VERSION 5.7 ;
BUSBITCHARS "[]" ;
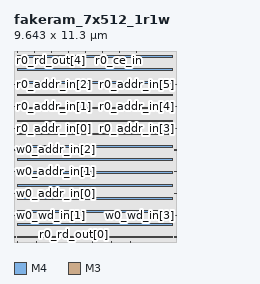
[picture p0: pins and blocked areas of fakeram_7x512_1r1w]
MACRO fakeram_7x512_1r1w
  FOREIGN fakeram_7x512_1r1w 0 0 ;
  SYMMETRY X Y R90 ;
  SIZE 9.643 BY 11.300 ;
  CLASS BLOCK ;
  PIN w0_wd_in[0]
    DIRECTION INPUT ;
    USE SIGNAL ;
    SHAPE ABUTMENT ;
    PORT
      LAYER M4 ;
      RECT 0.000 0.276 0.072 0.300 ;
    END
  END w0_wd_in[0]
  PIN w0_wd_in[1]
    DIRECTION INPUT ;
    USE SIGNAL ;
    SHAPE ABUTMENT ;
    PORT
      LAYER M4 ;
      RECT 0.000 1.572 0.072 1.596 ;
    END
  END w0_wd_in[1]
  PIN w0_wd_in[2]
    DIRECTION INPUT ;
    USE SIGNAL ;
    SHAPE ABUTMENT ;
    PORT
      LAYER M4 ;
      RECT 9.571 0.276 9.643 0.300 ;
    END
  END w0_wd_in[2]
  PIN w0_wd_in[3]
    DIRECTION INPUT ;
    USE SIGNAL ;
    SHAPE ABUTMENT ;
    PORT
      LAYER M4 ;
      RECT 9.571 1.572 9.643 1.596 ;
    END
  END w0_wd_in[3]
  PIN w0_wd_in[4]
    DIRECTION OUTPUT ;
    USE SIGNAL ;
    SHAPE ABUTMENT ;
    PORT
      LAYER M3 ;
      RECT 0.207 0.000 0.225 0.054 ;
    END
  END w0_wd_in[4]
  PIN w0_wd_in[5]
    DIRECTION OUTPUT ;
    USE SIGNAL ;
    SHAPE ABUTMENT ;
    PORT
      LAYER M3 ;
      RECT 1.323 0.000 1.341 0.054 ;
    END
  END w0_wd_in[5]
  PIN w0_wd_in[6]
    DIRECTION OUTPUT ;
    USE SIGNAL ;
    SHAPE ABUTMENT ;
    PORT
      LAYER M3 ;
      RECT 2.439 0.000 2.457 0.054 ;
    END
  END w0_wd_in[6]
  PIN r0_rd_out[0]
    DIRECTION OUTPUT ;
    USE SIGNAL ;
    SHAPE ABUTMENT ;
    PORT
      LAYER M3 ;
      RECT 3.555 0.000 3.573 0.054 ;
    END
  END r0_rd_out[0]
  PIN r0_rd_out[1]
    DIRECTION OUTPUT ;
    USE SIGNAL ;
    SHAPE ABUTMENT ;
    PORT
      LAYER M3 ;
      RECT 4.671 0.000 4.689 0.054 ;
    END
  END r0_rd_out[1]
  PIN r0_rd_out[2]
    DIRECTION OUTPUT ;
    USE SIGNAL ;
    SHAPE ABUTMENT ;
    PORT
      LAYER M3 ;
      RECT 5.787 0.000 5.805 0.054 ;
    END
  END r0_rd_out[2]
  PIN r0_rd_out[3]
    DIRECTION OUTPUT ;
    USE SIGNAL ;
    SHAPE ABUTMENT ;
    PORT
      LAYER M3 ;
      RECT 6.903 0.000 6.921 0.054 ;
    END
  END r0_rd_out[3]
  PIN r0_rd_out[4]
    DIRECTION OUTPUT ;
    USE SIGNAL ;
    SHAPE ABUTMENT ;
    PORT
      LAYER M3 ;
      RECT 0.207 11.246 0.225 11.300 ;
    END
  END r0_rd_out[4]
  PIN r0_rd_out[5]
    DIRECTION OUTPUT ;
    USE SIGNAL ;
    SHAPE ABUTMENT ;
    PORT
      LAYER M3 ;
      RECT 1.215 11.246 1.233 11.300 ;
    END
  END r0_rd_out[5]
  PIN r0_rd_out[6]
    DIRECTION OUTPUT ;
    USE SIGNAL ;
    SHAPE ABUTMENT ;
    PORT
      LAYER M3 ;
      RECT 2.223 11.246 2.241 11.300 ;
    END
  END r0_rd_out[6]
  PIN w0_addr_in[0]
    DIRECTION INPUT ;
    USE SIGNAL ;
    SHAPE ABUTMENT ;
    PORT
      LAYER M4 ;
      RECT 0.000 2.868 0.072 2.892 ;
    END
  END w0_addr_in[0]
  PIN w0_addr_in[1]
    DIRECTION INPUT ;
    USE SIGNAL ;
    SHAPE ABUTMENT ;
    PORT
      LAYER M4 ;
      RECT 0.000 4.164 0.072 4.188 ;
    END
  END w0_addr_in[1]
  PIN w0_addr_in[2]
    DIRECTION INPUT ;
    USE SIGNAL ;
    SHAPE ABUTMENT ;
    PORT
      LAYER M4 ;
      RECT 0.000 5.460 0.072 5.484 ;
    END
  END w0_addr_in[2]
  PIN w0_addr_in[3]
    DIRECTION INPUT ;
    USE SIGNAL ;
    SHAPE ABUTMENT ;
    PORT
      LAYER M4 ;
      RECT 9.571 2.868 9.643 2.892 ;
    END
  END w0_addr_in[3]
  PIN w0_addr_in[4]
    DIRECTION INPUT ;
    USE SIGNAL ;
    SHAPE ABUTMENT ;
    PORT
      LAYER M4 ;
      RECT 9.571 4.164 9.643 4.188 ;
    END
  END w0_addr_in[4]
  PIN w0_addr_in[5]
    DIRECTION INPUT ;
    USE SIGNAL ;
    SHAPE ABUTMENT ;
    PORT
      LAYER M4 ;
      RECT 9.571 5.460 9.643 5.484 ;
    END
  END w0_addr_in[5]
  PIN r0_addr_in[0]
    DIRECTION INPUT ;
    USE SIGNAL ;
    SHAPE ABUTMENT ;
    PORT
      LAYER M4 ;
      RECT 0.000 6.756 0.072 6.780 ;
    END
  END r0_addr_in[0]
  PIN r0_addr_in[1]
    DIRECTION INPUT ;
    USE SIGNAL ;
    SHAPE ABUTMENT ;
    PORT
      LAYER M4 ;
      RECT 0.000 8.052 0.072 8.076 ;
    END
  END r0_addr_in[1]
  PIN r0_addr_in[2]
    DIRECTION INPUT ;
    USE SIGNAL ;
    SHAPE ABUTMENT ;
    PORT
      LAYER M4 ;
      RECT 0.000 9.348 0.072 9.372 ;
    END
  END r0_addr_in[2]
  PIN r0_addr_in[3]
    DIRECTION INPUT ;
    USE SIGNAL ;
    SHAPE ABUTMENT ;
    PORT
      LAYER M4 ;
      RECT 9.571 6.756 9.643 6.780 ;
    END
  END r0_addr_in[3]
  PIN r0_addr_in[4]
    DIRECTION INPUT ;
    USE SIGNAL ;
    SHAPE ABUTMENT ;
    PORT
      LAYER M4 ;
      RECT 9.571 8.052 9.643 8.076 ;
    END
  END r0_addr_in[4]
  PIN r0_addr_in[5]
    DIRECTION INPUT ;
    USE SIGNAL ;
    SHAPE ABUTMENT ;
    PORT
      LAYER M4 ;
      RECT 9.571 9.348 9.643 9.372 ;
    END
  END r0_addr_in[5]
  PIN w0_we_in
    DIRECTION INPUT ;
    USE SIGNAL ;
    SHAPE ABUTMENT ;
    PORT
      LAYER M3 ;
      RECT 3.231 11.246 3.249 11.300 ;
    END
  END w0_we_in
  PIN w0_ce_in
    DIRECTION INPUT ;
    USE SIGNAL ;
    SHAPE ABUTMENT ;
    PORT
      LAYER M3 ;
      RECT 4.239 11.246 4.257 11.300 ;
    END
  END w0_ce_in
  PIN w0_clk
    DIRECTION INPUT ;
    USE SIGNAL ;
    SHAPE ABUTMENT ;
    PORT
      LAYER M3 ;
      RECT 5.247 11.246 5.265 11.300 ;
    END
  END w0_clk
  PIN r0_ce_in
    DIRECTION INPUT ;
    USE SIGNAL ;
    SHAPE ABUTMENT ;
    PORT
      LAYER M3 ;
      RECT 6.255 11.246 6.273 11.300 ;
    END
  END r0_ce_in
  PIN r0_clk
    DIRECTION INPUT ;
    USE SIGNAL ;
    SHAPE ABUTMENT ;
    PORT
      LAYER M3 ;
      RECT 7.263 11.246 7.281 11.300 ;
    END
  END r0_clk
  PIN VSS
    DIRECTION INOUT ;
    USE GROUND ;
    PORT
      LAYER M4 ;
      RECT 0.216 0.240 9.427 0.336 ;
      RECT 0.216 1.008 9.427 1.104 ;
      RECT 0.216 1.776 9.427 1.872 ;
      RECT 0.216 2.544 9.427 2.640 ;
      RECT 0.216 3.312 9.427 3.408 ;
      RECT 0.216 4.080 9.427 4.176 ;
      RECT 0.216 4.848 9.427 4.944 ;
      RECT 0.216 5.616 9.427 5.712 ;
      RECT 0.216 6.384 9.427 6.480 ;
      RECT 0.216 7.152 9.427 7.248 ;
      RECT 0.216 7.920 9.427 8.016 ;
      RECT 0.216 8.688 9.427 8.784 ;
      RECT 0.216 9.456 9.427 9.552 ;
      RECT 0.216 10.224 9.427 10.320 ;
      RECT 0.216 10.992 9.427 11.088 ;
    END
  END VSS
  PIN VDD
    DIRECTION INOUT ;
    USE POWER ;
    PORT
      LAYER M4 ;
      RECT 0.216 0.240 9.427 0.336 ;
      RECT 0.216 1.008 9.427 1.104 ;
      RECT 0.216 1.776 9.427 1.872 ;
      RECT 0.216 2.544 9.427 2.640 ;
      RECT 0.216 3.312 9.427 3.408 ;
      RECT 0.216 4.080 9.427 4.176 ;
      RECT 0.216 4.848 9.427 4.944 ;
      RECT 0.216 5.616 9.427 5.712 ;
      RECT 0.216 6.384 9.427 6.480 ;
      RECT 0.216 7.152 9.427 7.248 ;
      RECT 0.216 7.920 9.427 8.016 ;
      RECT 0.216 8.688 9.427 8.784 ;
      RECT 0.216 9.456 9.427 9.552 ;
      RECT 0.216 10.224 9.427 10.320 ;
      RECT 0.216 10.992 9.427 11.088 ;
    END
  END VDD
  OBS
    LAYER M1 ;
    RECT 0 0 9.643 11.300 ;
    LAYER M2 ;
    RECT 0 0 9.643 11.300 ;
    LAYER M3 ;
    RECT 0 0 9.643 11.300 ;
    LAYER M4 ;
    RECT 0 0 9.643 11.300 ;
  END
END fakeram_7x512_1r1w

END LIBRARY
